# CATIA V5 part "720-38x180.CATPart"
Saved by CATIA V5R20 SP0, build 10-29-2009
Part number: 720-38x180
Definition: NONE
Nomenclature: 720-38x180
Source: Unknown
Description: 720-38x180
Bounding box of the stored display mesh (mm): x 0 to 180, y -19 to 19, z -19 to 19
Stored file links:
  C:\Users\Utente\Desktop\IO LAVORO\3D X SITO CF\X SITO\720\720-38x180.CATPart

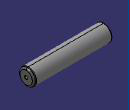
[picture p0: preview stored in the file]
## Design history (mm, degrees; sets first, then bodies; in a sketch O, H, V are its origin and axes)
Body1 "720-38x180" (main body)
  Solid1: solid without history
